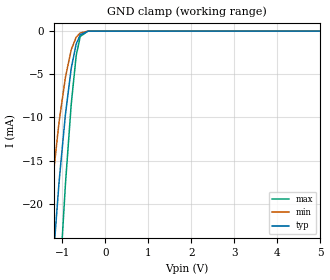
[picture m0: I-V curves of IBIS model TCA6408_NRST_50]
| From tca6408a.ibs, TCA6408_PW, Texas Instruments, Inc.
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[Model]   TCA6408_NRST_50
Model_type  Input
Vinl=1.35
Vinh=3.85
| variable   typ   min   max
C_comp   2.17pF   1.80pF   2.32pF
[Temperature Range]   40   100   -40
| Ambient temperature   25   85   -40
[Voltage range]   5   4.5   5.5
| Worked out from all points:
|   GND clamp passes 1 mA (typ) near -0.65 V on its own axis
[GND Clamp]
| TCA6408_NRST_50
|   Voltage   I(typ)   I(min)   I(max)
-5V       -421.5mA   -327.2mA   -555.2mA
-1.48V    -46.19mA   -30.98mA   -72.79mA
-1.435V   -42.57mA   -28.34mA   -67.61mA
-1.265V   -29.76mA   -19.1mA    -48.89mA
-1.085V   -17.96mA   -10.85mA   -30.98mA
-1.065V   -16.78mA   -10.05mA   -29.14mA
-930mV    -9.662mA   -5.357mA   -17.73mA
-795mV    -4.307mA   -2.154mA   -8.462mA
-680mV    -1.498mA   -708.4uA   -2.836mA
-585mV    -416.3uA   -213.5uA   -615.5uA
-405mV    -11.9uA    -9.596uA   -9.604uA
5V        572.5pA    2.003nA    91.86pA
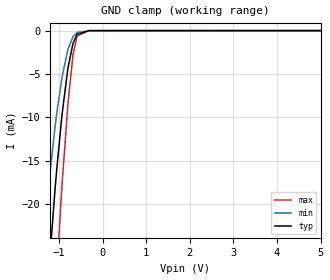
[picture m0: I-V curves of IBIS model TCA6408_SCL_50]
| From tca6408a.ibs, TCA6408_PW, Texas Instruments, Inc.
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[Model]   TCA6408_SCL_50
Model_type  Input
Vinl=1.35
Vinh=3.85
| variable   typ   min   max
C_comp   2.12pF   1.76pF   2.26pF
[Temperature Range]   40   100   -40
| Ambient temperature   25   85   -40
[Voltage range]   5   4.5   5.5
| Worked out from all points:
|   GND clamp passes 1 mA (typ) near -0.65 V on its own axis
[GND Clamp]
| TCA6408_SCL_50
|   Voltage   I(typ)   I(min)   I(max)
-5V       -421.5mA   -327.2mA   -555.2mA
-1.48V    -46.19mA   -30.98mA   -72.8mA
-1.435V   -42.58mA   -28.34mA   -67.61mA
-1.265V   -29.77mA   -19.11mA   -48.89mA
-1.085V   -17.96mA   -10.85mA   -30.98mA
-1.05V    -15.92mA   -9.467mA   -27.79mA
-930mV    -9.667mA   -5.361mA   -17.73mA
-795mV    -4.311mA   -2.158mA   -8.467mA
-680mV    -1.503mA   -712.6uA   -2.841mA
-585mV    -421uA     -217.3uA   -621uA
-310mV    -3.791uA   -3.288uA   -3.906uA
5V        572.5pA    3.503uA    -5.522uA
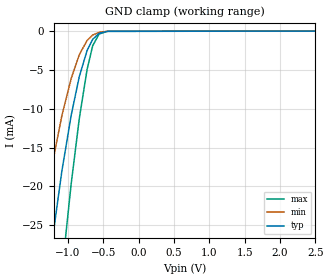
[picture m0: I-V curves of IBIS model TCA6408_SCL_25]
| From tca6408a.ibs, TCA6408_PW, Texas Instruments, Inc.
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[Model]   TCA6408_SCL_25
Model_type  Input
Vinl=0.69
Vinh=1.89
| variable   typ   min   max
C_comp   2.19pF   1.68pF   2.42pF
[Temperature Range]   40   100   -40
| Ambient temperature   25   85   -40
[Voltage range]   2.5   2.3   2.7
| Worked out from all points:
|   GND clamp passes 1 mA (typ) near -0.65 V on its own axis
[GND Clamp]
| TCA6408_SCL_25
|   Voltage   I(typ)   I(min)   I(max)
-2.5V     -143.4mA   -105mA     -204.1mA
-1.49V    -47.01mA   -31.58mA   -73.96mA
-1.46V    -44.57mA   -29.8mA    -70.48mA
-1.27V    -30.12mA   -19.36mA   -49.42mA
-1.085V   -17.96mA   -10.85mA   -30.98mA
-955mV    -10.86mA   -6.127mA   -19.7mA
-840mV    -5.87mA    -3.043mA   -11.28mA
-730mV    -2.509mA   -1.205mA   -4.961mA
-650mV    -1.053mA   -502.7uA   -1.883mA
-560mV    -279.8uA   -153.1uA   -377.5uA
-440mV    -30.06uA   -22.66uA   -28.84uA
2.5V      205.9pA    1.388uA    -2.198uA
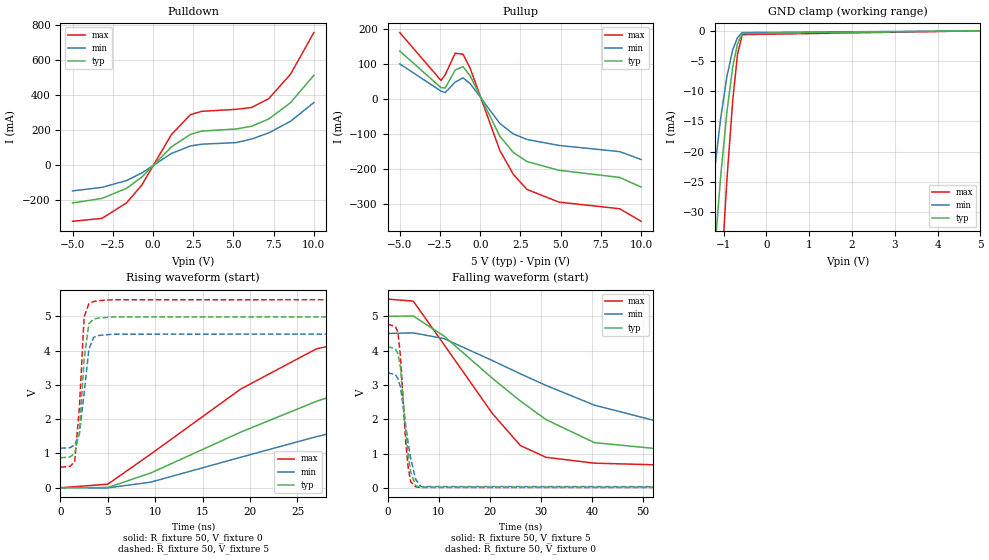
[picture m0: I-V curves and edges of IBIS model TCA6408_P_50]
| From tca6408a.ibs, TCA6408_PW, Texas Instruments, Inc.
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[Model]   TCA6408_P_50
Model_type  I/O
Vinl=1.35
Vinh=3.85
Enable   Active-Low
Vref =   0
Rref =   500
Cref =   50p
Vmeas =   2.5
| variable   typ   min   max
C_comp   3.63pF   2.93pF   3.99pF
| C_pullup   6.60pF   2.64pF   9.47pF
| C_pulldown   4.28pF   3.34pF   5.80pF
| C_tri-state   3.63pF   2.93pF   3.99pF
[Temperature Range]   40   100   -40
| Ambient temperature   25   85   -40
[Voltage range]   5   4.5   5.5
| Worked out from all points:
|   slope of the pulldown table from 0 to 0.75 V, typ, clamps not added: 10.5 ohm
|   slope of the pullup table from 0 to 0.75 V, typ, clamps not added: 10.5 ohm
|   GND clamp passes 1 mA (typ) near -0.61 V on its own axis
|   rising waveform, R_fixture 50, V_fixture 0: 20-80 % time 23.3ns typ, 32.9ns min, 15.6ns max; typ from 0 V to 4.12 V
|   falling waveform, R_fixture 50, V_fixture 5: 20-80 % time 21.2ns typ, 34.1ns min, 14.2ns max; typ from 5 V to 0.876 V
|   rising waveform, R_fixture 50, V_fixture 5: 20-80 % time 684ps typ, 812ps min, 654ps max; typ from 0.876 V to 5 V
|   falling waveform, R_fixture 50, V_fixture 0: 20-80 % time 1.53ns typ, 2.01ns min, 1.27ns max; typ from 4.12 V to 0 V
[GND Clamp]
| TCA6408_P_50
|   Voltage   I(typ)   I(min)   I(max)
-5V       -590mA     -448.8mA   -795mA
-1.51V    -68.12mA   -45.25mA   -108.4mA
-1.465V   -63.04mA   -41.61mA   -101mA
-1.29V    -44.47mA   -28.47mA   -73.42mA
-1.25V    -40.52mA   -25.71mA   -67.44mA
-1.075V   -24.76mA   -14.94mA   -43.03mA
-1.06V    -23.54mA   -14.13mA   -41.1mA
-920mV    -13.34mA   -7.513mA   -24.47mA
-785mV    -5.952mA   -3.123mA   -11.49mA
-675mV    -2.175mA   -1.137mA   -3.955mA
-565mV    -467.5uA   -292.1uA   -632uA
5V        1.249nA    3.317nA    448pA
[Pulldown]
| TCA6408_P_50
|   Voltage   I(typ)   I(min)   I(max)
-5V       -216.3mA   -147.4mA   -321.1mA
-3.17V    -190.5mA   -127.2mA   -304.5mA
-1.635V   -132.3mA   -88.14mA   -215.2mA
-695mV    -68.89mA   -45.25mA   -114.4mA
1.14V     103.7mA    66.3mA     173.6mA
2.33V     175.5mA    109.3mA    288.5mA
3.04V     194.5mA    119.6mA    307.4mA
5.175V    206.5mA    128.6mA    318.7mA
6.135V    222mA      148.8mA    329.3mA
7.2V      263.7mA    184.3mA    379.8mA
8.55V     356.6mA    250.3mA    519.1mA
10V       512.8mA    357.4mA    757.3mA
[Pullup]
| TCA6408_P_50
|   Voltage   I(typ)   I(min)   I(max)
-5V       135.9mA    99.31mA    188.6mA
-2.44V    31.7mA     21.81mA    52.05mA
-2.175V   30.45mA    17.66mA    68.46mA
-1.555V   81.88mA    47.36mA    129.8mA
-1.07V    91.37mA    59.47mA    127mA
-620mV    64.88mA    42.88mA    86.27mA
1.22V     -107.1mA   -70.5mA    -147.6mA
2.055V    -153mA     -100.3mA   -215.4mA
2.91V     -179.1mA   -116.2mA   -258.8mA
4.9V      -204mA     -133.2mA   -294.7mA
8.665V    -224.3mA   -150.7mA   -313.6mA
10V       -251.7mA   -173.2mA   -349.4mA
[Ramp]
| TCA6408_P_50
| variable   typ   min   max
dV/dt_r   2.50/2.35E-08   2.04/3.31E-08   2.90/1.57E-08
dV/dt_f   2.49/2.13E-08   2.02/3.41E-08   2.96/1.43E-08
R_load = 50
[Rising Waveform]
| TCA6408_P_50
R_fixture =   50
C_fixture =   0
L_fixture =   0
V_fixture =   0
V_fixture_min = 0
V_fixture_max = 0
|   Time   V(typ)   V(min)   V(max)
0s        3.746nV    27.75nV    804.2pV
5ns       9.165mV    -3.401mV   104.3mV
9.5ns     426.5mV    162mV      976.1mV
19ns      1.62V      887.4mV    2.876V
27ns      2.52V      1.49V      4.051V
33.5ns    3.109V     1.919V     4.439V
44.5ns    3.691V     2.497V     4.631V
67ns      3.99V      3.081V     4.732V
111ns     4.096V     3.3V       4.766V
520ns     4.118V     3.355V     4.771V
[Falling Waveform]
| TCA6408_P_50
R_fixture =   50
C_fixture =   0
L_fixture =   0
V_fixture =   5
V_fixture_min = 4.5
V_fixture_max = 5.5
|   Time   V(typ)   V(min)   V(max)
0s        5V         4.5V       5.5V
5ns       5.008V     4.516V     5.442V
11ns      4.426V     4.351V     4.182V
20.5ns    3.193V     3.71V      2.167V
26ns      2.53V      3.323V     1.231V
31ns      1.99V      2.986V     891.7mV
40.5ns    1.318V     2.409V     719.4mV
63.5ns    985mV      1.537V     628.3mV
105ns     896.1mV    1.237V     602.6mV
520ns     876.2mV    1.153V     598.2mV
[Rising Waveform]
| TCA6408_P_50
R_fixture =   50
C_fixture =   0
L_fixture =   0
V_fixture =   5
V_fixture_min = 4.5
V_fixture_max = 5.5
|   Time   V(typ)   V(min)   V(max)
0s        876.1mV    1.153V     598.2mV
1ns       895.7mV    1.166V     621.7mV
1.5ns     1V         1.25V      752.9mV
2ns       1.614V     1.569V     2.349V
2.5ns     3.752V     2.756V     4.982V
3ns       4.788V     4.04V      5.368V
3.5ns     4.916V     4.384V     5.431V
4ns       4.947V     4.44V      5.455V
5.5ns     4.979V     4.478V     5.481V
520ns     5V         4.5V       5.5V
[Falling Waveform]
| TCA6408_P_50
R_fixture =   50
C_fixture =   0
L_fixture =   0
V_fixture =   0
V_fixture_min = 0
V_fixture_max = 0
|   Time   V(typ)   V(min)   V(max)
0s        4.118V     3.355V     4.771V
1.5ns     4.05V      3.299V     4.702V
2ns       3.909V     3.188V     4.533V
2.5ns     3.511V     2.934V     3.832V
3.5ns     1.715V     1.853V     1.391V
4ns       983.7mV    1.311V     610.2mV
4.5ns     468.5mV    853.7mV    176.7mV
5.5ns     55.18mV    243.8mV    28.68mV
6.5ns     17.66mV    37.94mV    12.63mV
520ns     62.97nV    252nV      35.55nV
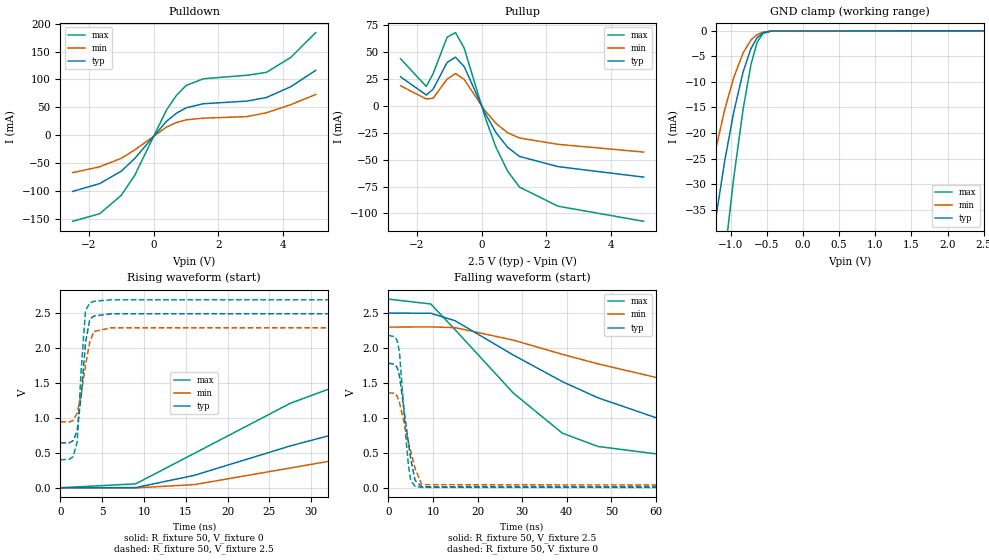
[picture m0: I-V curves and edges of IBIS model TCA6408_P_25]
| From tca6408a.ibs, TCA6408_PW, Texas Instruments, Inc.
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[Model]   TCA6408_P_25
Model_type  I/O
Vinl=0.69
Vinh=1.89
Enable   Active-Low
Vref =   0
Rref =   500
Cref =   50p
Vmeas =   1.25
| variable   typ   min   max
C_comp   3.69pF   2.93pF   4.10pF
| C_pullup   6.79pF   2.74pF   10.86pF
| C_pulldown   4.46pF   3.36pF   6.24pF
| C_tri-state   3.69pF   2.93pF   4.10pF
[Temperature Range]   40   100   -40
| Ambient temperature   25   85   -40
[Voltage range]   2.5   2.3   2.7
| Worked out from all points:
|   slope of the pulldown table from 0 to 0.375 V, typ, clamps not added: 15.6 ohm
|   slope of the pullup table from 0 to 0.375 V, typ, clamps not added: 17.4 ohm
|   GND clamp passes 1 mA (typ) near -0.61 V on its own axis
|   rising waveform, R_fixture 50, V_fixture 0: 20-80 % time 39.1ns typ, 55.9ns min, 24.3ns max; typ from 0 V to 1.78 V
|   falling waveform, R_fixture 50, V_fixture 2.5: 20-80 % time 37.3ns typ, 65.3ns min, 21.8ns max; typ from 2.5 V to 0.642 V
|   rising waveform, R_fixture 50, V_fixture 2.5: 20-80 % time 889ps typ, 1.16ns min, 722ps max; typ from 0.642 V to 2.5 V
|   falling waveform, R_fixture 50, V_fixture 0: 20-80 % time 2.26ns typ, 3.04ns min, 1.59ns max; typ from 1.78 V to 0 V
[GND Clamp]
| TCA6408_P_25
|   Voltage   I(typ)   I(min)   I(max)
-2.5V     -199.5mA   -143mA     -290.2mA
-1.495V   -66.41mA   -44.03mA   -105.9mA
-1.3V     -45.47mA   -29.17mA   -74.94mA
-1.275V   -42.97mA   -27.43mA   -71.16mA
-1.085V   -25.59mA   -15.5mA    -44.34mA
-960mV    -16.02mA   -9.208mA   -28.93mA
-830mV    -8.107mA   -4.347mA   -15.43mA
-720mV    -3.455mA   -1.786mA   -6.597mA
-635mV    -1.338mA   -725.2uA   -2.246mA
-555mV    -393.8uA   -252.8uA   -513.9uA
-435mV    -36.87uA   -30.65uA   -32.48uA
2.5V      522.1pA    1.492nA    -263.6pA
[Pulldown]
| TCA6408_P_25
|   Voltage   I(typ)   I(min)   I(max)
-2.5V     -100.3mA   -66.72mA   -153.8mA
-1.665V   -86.32mA   -56.23mA   -140.3mA
-995mV    -63.91mA   -40.95mA   -107mA
-580mV    -41.14mA   -25.84mA   -71.06mA
400mV     25.38mA    15.01mA    45.82mA
705mV     39.76mA    23.05mA    71.75mA
1.005V    49.41mA    27.82mA    89.36mA
1.53V     56.6mA     30.79mA    101.3mA
2.88V     61.37mA    33.64mA    107.6mA
3.48V     67.85mA    40.52mA    112.8mA
4.23V     87.1mA     55.01mA    139.6mA
5V        116.4mA    73.18mA    184mA
[Pullup]
| TCA6408_P_25
|   Voltage   I(typ)   I(min)   I(max)
-2.5V     27.05mA    18.71mA    43.88mA
-1.705V   10.14mA    6.404mA    18.04mA
-1.495V   15.53mA    7.156mA    29.94mA
-1.065V   40.3mA     24.79mA    63.75mA
-805mV    45.35mA    30.16mA    68.19mA
-535mV    36.51mA    24.55mA    53.62mA
105mV     -6.664mA   -4.379mA   -10.22mA
445mV     -24.83mA   -16.25mA   -38.52mA
805mV     -38.57mA   -24.98mA   -60.74mA
1.17V     -46.99mA   -29.85mA   -75.51mA
2.36V     -56.47mA   -35.74mA   -93.28mA
5V        -66.2mA    -42.93mA   -107.3mA
[Ramp]
| TCA6408_P_25
| variable   typ   min   max
dV/dt_r   1.09/3.93E-08   0.83/5.61E-08   1.33/2.46E-08
dV/dt_f   1.12/3.74E-08   0.82/6.54E-08   1.39/2.19E-08
R_load = 50
[Rising Waveform]
| TCA6408_P_25
R_fixture =   50
C_fixture =   0
L_fixture =   0
V_fixture =   0
V_fixture_min = 0
V_fixture_max = 0
|   Time   V(typ)   V(min)   V(max)
0s        1.68nV     12.67nV    504.7pV
9ns       2.519mV    -1.473mV   55.94mV
16ns      177mV      44.79mV    491mV
27.5ns    598.7mV    282.8mV    1.209V
40ns      995.2mV    542.7mV    1.762V
50.5ns    1.252V     725.2mV    1.987V
65.5ns    1.504V     926.8mV    2.099V
103ns     1.718V     1.206V     2.167V
156ns     1.773V     1.325V     2.181V
520ns     1.784V     1.361V     2.182V
[Falling Waveform]
| TCA6408_P_25
R_fixture =   50
C_fixture =   0
L_fixture =   0
V_fixture =   2.5
V_fixture_min = 2.3
V_fixture_max = 2.7
|   Time   V(typ)   V(min)   V(max)
0s        2.5V       2.3V       2.7V
9.5ns     2.498V     2.303V     2.631V
15ns      2.39V      2.292V     2.261V
28ns      1.901V     2.114V     1.358V
39ns      1.521V     1.911V     783.6mV
47ns      1.289V     1.774V     592.1mV
60.5ns    993.3mV    1.573V     482.8mV
92ns      733mV      1.256V     419.7mV
162ns     651mV      1.006V     402.6mV
520ns     642mV      944.6mV    401.5mV
[Rising Waveform]
| TCA6408_P_25
R_fixture =   50
C_fixture =   0
L_fixture =   0
V_fixture =   2.5
V_fixture_min = 2.3
V_fixture_max = 2.7
|   Time   V(typ)   V(min)   V(max)
0s        642mV      944.5mV    401.5mV
1ns       641.2mV    940.2mV    403.8mV
1.5ns     672.1mV    960.9mV    442.7mV
2ns       812.6mV    1.068V     654.7mV
2.5ns     1.335V     1.353V     1.719V
3ns       2.074V     1.753V     2.537V
3.5ns     2.406V     2.083V     2.644V
4ns       2.458V     2.237V     2.669V
6ns       2.49V      2.289V     2.69V
520ns     2.5V       2.3V       2.7V
[Falling Waveform]
| TCA6408_P_25
R_fixture =   50
C_fixture =   0
L_fixture =   0
V_fixture =   0
V_fixture_min = 0
V_fixture_max = 0
|   Time   V(typ)   V(min)   V(max)
0s        1.784V     1.361V     2.182V
1.5ns     1.767V     1.351V     2.161V
2ns       1.715V     1.308V     2.099V
2.5ns     1.599V     1.219V     1.937V
4ns       884.2mV    803.3mV    671.8mV
4.5ns     638.8mV    661.7mV    324.7mV
5ns       419.2mV    524.6mV    105.8mV
6ns       107.5mV    277.5mV    22.03mV
7.5ns     14.57mV    45.42mV    7.227mV
520ns     81.62nV    304.4nV    43.18nV
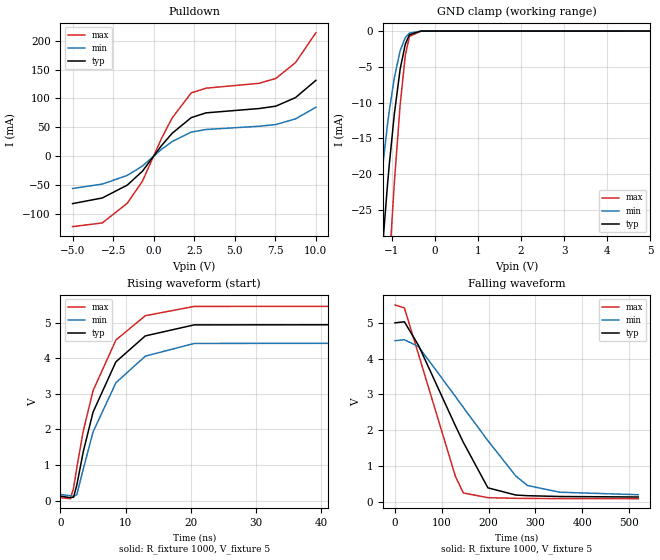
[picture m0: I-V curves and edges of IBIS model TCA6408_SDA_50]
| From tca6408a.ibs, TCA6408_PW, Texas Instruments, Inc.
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[Model]   TCA6408_SDA_50
Model_type  I/O_open_drain
Vinl=1.35
Vinh=3.85
Enable   Active-Low
Vref =   5
Rref =   1000
Cref =   50p
Vmeas =   2.5
| variable   typ   min   max
C_comp   3.07pF   2.23pF   3.44pF
| C_pulldown   1.95pF   0.78pF   2.55pF
| C_tri-state   3.07pF   2.23pF   3.44pF
[Temperature Range]   40   100   -40
| Ambient temperature   25   85   -40
[Voltage range]   5   4.5   5.5
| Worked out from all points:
|   slope of the pulldown table from 0 to 0.75 V, typ, clamps not added: 27.4 ohm
|   GND clamp passes 1 mA (typ) near -0.63 V on its own axis
|   rising waveform, R_fixture 1000, V_fixture 5: 20-80 % time 5.79ns typ, 6.26ns min, 5.42ns max; typ from 0.125 V to 5 V
|   falling waveform, R_fixture 1000, V_fixture 5: 20-80 % time 104ns typ, 146ns min, 74.6ns max; typ from 5 V to 0.129 V
[GND Clamp]
| TCA6408_SDA_50
|   Voltage   I(typ)   I(min)   I(max)
-5V       -485.9mA   -373.7mA   -646.7mA
-1.495V   -54.71mA   -36.56mA   -86.57mA
-1.45V    -50.53mA   -33.53mA   -80.53mA
-1.28V    -35.7mA    -22.93mA   -58.7mA
-1.09V    -21.25mA   -12.89mA   -36.66mA
-1.055V   -18.89mA   -11.29mA   -32.94mA
-935mV    -11.62mA   -6.534mA   -21.21mA
-800mV    -5.319mA   -2.744mA   -10.32mA
-680mV    -1.821mA   -907.7uA   -3.383mA
-585mV    -514.7uA   -286.1uA   -750.7uA
-315mV    -4.283uA   -3.819uA   -4.181uA
5V        768.1pA    3.503uA    -5.521uA
[Pulldown]
| TCA6408_SDA_50
|   Voltage   I(typ)   I(min)   I(max)
-5V       -82.45mA   -56.22mA   -122.3mA
-3.17V    -72.66mA   -48.53mA   -116mA
-1.63V    -50.38mA   -33.58mA   -81.84mA
-695mV    -26.29mA   -17.29mA   -43.61mA
470mV     17.72mA    11.43mA    29.85mA
1.135V    39.44mA    25.23mA    65.94mA
2.315V    66.7mA     41.58mA    109.6mA
3.235V    75mA       46.11mA    117.8mA
6.495V    82.46mA    51.74mA    126.2mA
7.53V     86.58mA    54.63mA    134.6mA
8.745V    101.4mA    64.52mA    162.1mA
10V       131.3mA    84.61mA    213.8mA
[Ramp]
| TCA6408_SDA_50
| variable   typ   min   max
dV/dt_r   2.95/5.80E-09   2.63/6.26E-09   3.27/5.42E-09
dV/dt_f   2.94/1.05E-07   2.60/1.47E-07   3.28/7.51E-08
R_load = 1000
[Rising Waveform]
| TCA6408_SDA_50
R_fixture =   1000
C_fixture =   0
L_fixture =   0
V_fixture =   5
V_fixture_min = 4.5
V_fixture_max = 5.5
|   Time   V(typ)   V(min)   V(max)
0s        124.5mV    171.8mV    81.52mV
1.5ns     81.82mV    137.7mV    52.73mV
2ns       91.96mV    115.1mV    337mV
2.5ns     427.7mV    165mV      915.6mV
3.5ns     1.377V     887.7mV    1.959V
5ns       2.488V     1.932V     3.091V
8.5ns     3.901V     3.312V     4.514V
13ns      4.629V     4.06V      5.197V
20.5ns    4.939V     4.417V     5.458V
520ns     5V         4.5V       5.5V
[Falling Waveform]
| TCA6408_SDA_50
R_fixture =   1000
C_fixture =   0
L_fixture =   0
V_fixture =   5
V_fixture_min = 4.5
V_fixture_max = 5.5
|   Time   V(typ)   V(min)   V(max)
0s        5V         4.5V       5.5V
20ns      5.028V     4.527V     5.415V
50.5ns    4.359V     4.33V      4.103V
129ns     2.122V     2.941V     708.7mV
146ns     1.657V     2.634V     242.9mV
198.5ns   386.5mV    1.706V     110.8mV
258ns     184.7mV    719.4mV    93.01mV
283ns     166.3mV    451.8mV    89.96mV
352ns     143.8mV    263.7mV    85.57mV
520ns     129.5mV    193.7mV    82.43mV
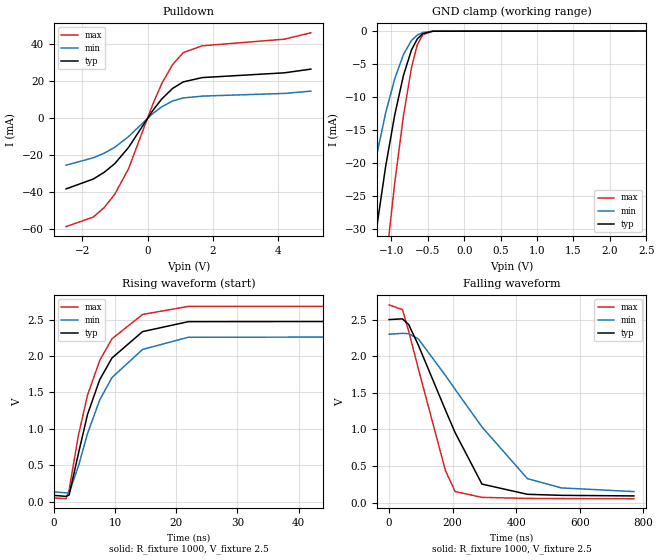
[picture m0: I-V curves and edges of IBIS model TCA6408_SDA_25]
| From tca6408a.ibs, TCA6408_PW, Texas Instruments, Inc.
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[Model]   TCA6408_SDA_25
Model_type  I/O_open_drain
Vinl=0.69
Vinh=1.89
Enable   Active-Low
Vref =   2.5
Rref =   1000
Cref =   50p
Vmeas =   1.25
| variable   typ   min   max
C_comp   3.07pF   2.07pF   3.54pF
| C_pulldown   1.93pF   0.80pF   2.67pF
| C_tri-state   3.07pF   2.07pF   3.54pF
[Temperature Range]   40   100   -40
| Ambient temperature   25   85   -40
[Voltage range]   2.5   2.3   2.7
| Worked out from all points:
|   slope of the pulldown table from 0 to 0.375 V, typ, clamps not added: 41 ohm
|   GND clamp passes 1 mA (typ) near -0.63 V on its own axis
|   rising waveform, R_fixture 1000, V_fixture 2.5: 20-80 % time 6.1ns typ, 6.8ns min, 5.64ns max; typ from 0.09 V to 2.5 V
|   falling waveform, R_fixture 1000, V_fixture 2.5: 20-80 % time 143ns typ, 217ns min, 96ns max; typ from 2.5 V to 0.092 V
[GND Clamp]
| TCA6408_SDA_25
|   Voltage   I(typ)   I(min)   I(max)
-2.5V     -164.9mA   -119.6mA   -237mA
-1.49V    -54.24mA   -36.22mA   -85.89mA
-1.46V    -51.45mA   -34.2mA    -81.86mA
-1.27V    -34.88mA   -22.35mA   -57.47mA
-1.08V    -20.56mA   -12.43mA   -35.58mA
-955mV    -12.73mA   -7.245mA   -23.03mA
-835mV    -6.732mA   -3.552mA   -12.86mA
-725mV    -2.878mA   -1.436mA   -5.585mA
-645mV    -1.203mA   -611.4uA   -2.091mA
-570mV    -404.1uA   -233uA     -558.9uA
-435mV    -32.77uA   -26.06uA   -30.49uA
2.5V      294.5pA    1.389uA    -2.198uA
[Pulldown]
| TCA6408_SDA_25
|   Voltage   I(typ)   I(min)   I(max)
-2.5V     -38.21mA   -25.41mA   -58.57mA
-1.665V   -32.88mA   -21.42mA   -53.42mA
-1.325V   -29.17mA   -18.87mA   -48.19mA
-1.005V   -24.53mA   -15.72mA   -41.01mA
-585mV    -15.82mA   -9.947mA   -27.3mA
150mV     3.947mA    2.363mA    7.134mA
430mV     10.3mA     6.081mA    18.57mA
765mV     16.04mA    9.25mA     28.93mA
1.09V     19.56mA    10.9mA     35.38mA
1.67V     21.89mA    11.89mA    39.05mA
4.19V     24.47mA    13.35mA    42.64mA
5V        26.46mA    14.57mA    46.07mA
[Ramp]
| TCA6408_SDA_25
| variable   typ   min   max
dV/dt_r   1.46/6.10E-09   1.31/6.81E-09   1.60/5.65E-09
dV/dt_f   1.45/1.44E-07   1.30/2.19E-07   1.60/9.67E-08
R_load = 1000
[Rising Waveform]
| TCA6408_SDA_25
R_fixture =   1000
C_fixture =   0
L_fixture =   0
V_fixture =   2.5
V_fixture_min = 2.3
V_fixture_max = 2.7
|   Time   V(typ)   V(min)   V(max)
0s        89.88mV    136.6mV    53.97mV
2ns       74.75mV    124.7mV    43.78mV
2.5ns     93.76mV    124.2mV    164.6mV
4ns       655.8mV    486.5mV    904.5mV
5.5ns     1.197V     935mV      1.462V
7.5ns     1.675V     1.398V     1.939V
9.5ns     1.972V     1.704V     2.236V
14.5ns    2.334V     2.09V      2.569V
22ns      2.471V     2.257V     2.68V
520ns     2.5V       2.3V       2.7V
[Falling Waveform]
| TCA6408_SDA_25
R_fixture =   1000
C_fixture =   0
L_fixture =   0
V_fixture =   2.5
V_fixture_min = 2.3
V_fixture_max = 2.7
|   Time   V(typ)   V(min)   V(max)
0s        2.5V       2.3V       2.7V
42ns      2.51V      2.312V     2.636V
61.5ns    2.432V     2.307V     2.341V
92ns      2.15V      2.235V     1.827V
177ns     1.265V     1.738V     440.2mV
207.5ns   957.5mV    1.547V     152.3mV
292ns     253.7mV    1.034V     72.29mV
435ns     114.2mV    327.8mV    58.01mV
542ns     100.1mV    201.5mV    55.58mV
770ns     92.05mV    151.3mV    54.23mV
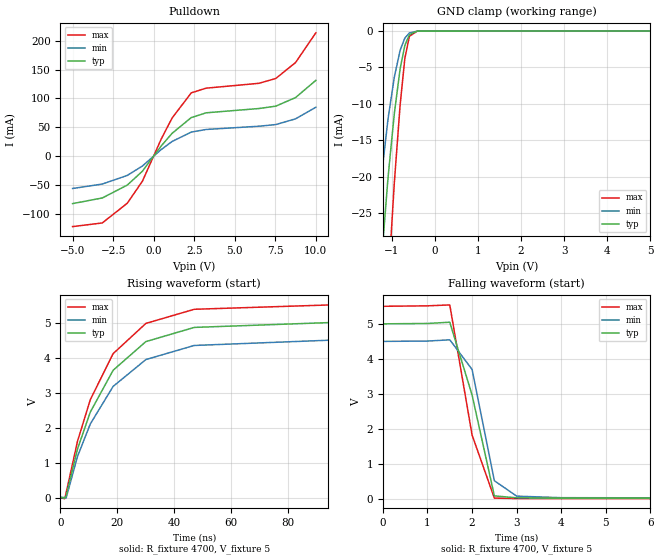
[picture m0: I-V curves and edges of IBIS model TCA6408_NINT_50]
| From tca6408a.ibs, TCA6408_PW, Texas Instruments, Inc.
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[Model]   TCA6408_NINT_50
Model_type  Open_drain
Enable   Active-Low
Vref =   5
Rref =   4700
Cref =   50p
Vmeas =   2.5
| variable   typ   min   max
C_comp   2.28pF   1.90pF   2.46pF
| C_pulldown   2.95pF   2.20pF   3.72pF
| C_tri-state   2.28pF   1.90pF   2.46pF
[Temperature Range]   40   100   -40
| Ambient temperature   25   85   -40
[Voltage range]   5   4.5   5.5
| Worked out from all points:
|   slope of the pulldown table from 0 to 0.75 V, typ, clamps not added: 27.4 ohm
|   GND clamp passes 1 mA (typ) near -0.63 V on its own axis
|   rising waveform, R_fixture 4700, V_fixture 5: 20-80 % time 17.8ns typ, 18.7ns min, 16.9ns max; typ from 0.027 V to 5 V
|   falling waveform, R_fixture 4700, V_fixture 5: 20-80 % time 588ps typ, 422ps min, 547ps max; typ from 5 V to 0.027 V
[GND Clamp]
| TCA6408_NINT_50
|   Voltage   I(typ)   I(min)   I(max)
-5V       -479.6mA   -367.9mA   -640.3mA
-1.495V   -53.75mA   -35.77mA   -85.47mA
-1.45V    -49.64mA   -32.8mA    -79.5mA
-1.28V    -35.02mA   -22.38mA   -57.9mA
-1.09V    -20.8mA    -12.54mA   -36.1mA
-1.07V    -19.46mA   -11.64mA   -33.99mA
-935mV    -11.34mA   -6.326mA   -20.84mA
-800mV    -5.162mA   -2.633mA   -10.11mA
-690mV    -1.955mA   -955.9uA   -3.719mA
-585mV    -489.4uA   -264.7uA   -718.6uA
-405mV    -14.02uA   -11.66uA   -11.19uA
5V        727.1pA    2.224nA    203.5pA
[Pulldown]
| TCA6408_NINT_50
|   Voltage   I(typ)   I(min)   I(max)
-5V       -82.53mA   -56.3mA    -122.4mA
-3.17V    -72.74mA   -48.6mA    -116.1mA
-1.63V    -50.43mA   -33.63mA   -81.91mA
-695mV    -26.31mA   -17.3mA    -43.63mA
465mV     17.55mA    11.31mA    29.55mA
1.13V     39.3mA     25.14mA    65.7mA
2.315V    66.7mA     41.58mA    109.6mA
3.235V    75mA       46.11mA    117.8mA
6.495V    82.46mA    51.74mA    126.2mA
7.53V     86.58mA    54.63mA    134.6mA
8.745V    101.4mA    64.52mA    162.1mA
10V       131.3mA    84.61mA    213.8mA
[Ramp]
| TCA6408_NINT_50
| variable   typ   min   max
dV/dt_r   3.00/1.78E-08   2.70/1.87E-08   3.31/1.69E-08
dV/dt_f   3.01/3.13E-10   2.71/3.95E-10   3.32/2.52E-10
R_load = 4700
[Rising Waveform]
| TCA6408_NINT_50
R_fixture =   4700
C_fixture =   0
L_fixture =   0
V_fixture =   5
V_fixture_min = 4.5
V_fixture_max = 5.5
|   Time   V(typ)   V(min)   V(max)
0s        26.77mV    37.14mV    17.43mV
1.5ns     11.55mV    26.23mV    -6.238mV
2ns       76.59mV    12.65mV    161.8mV
6ns       1.407V     1.196V     1.628V
10.5ns    2.457V     2.119V     2.81V
18.5ns    3.643V     3.184V     4.115V
30ns      4.457V     3.947V     4.974V
47ns      4.861V     4.348V     5.376V
94ns      4.997V     4.496V     5.498V
520ns     5V         4.5V       5.5V
[Falling Waveform]
| TCA6408_NINT_50
R_fixture =   4700
C_fixture =   0
L_fixture =   0
V_fixture =   5
V_fixture_min = 4.5
V_fixture_max = 5.5
|   Time   V(typ)   V(min)   V(max)
0s        5V         4.5V       5.5V
1ns       5.011V     4.509V     5.513V
1.5ns     5.046V     4.545V     5.539V
2ns       2.973V     3.701V     1.833V
2.5ns     98.49mV    529.8mV    33.55mV
3ns       41.28mV    90.26mV    22.47mV
4ns       30.22mV    46.1mV     18.82mV
9ns       26.9mV     37.42mV    17.48mV
520ns     26.77mV    37.14mV    17.43mV
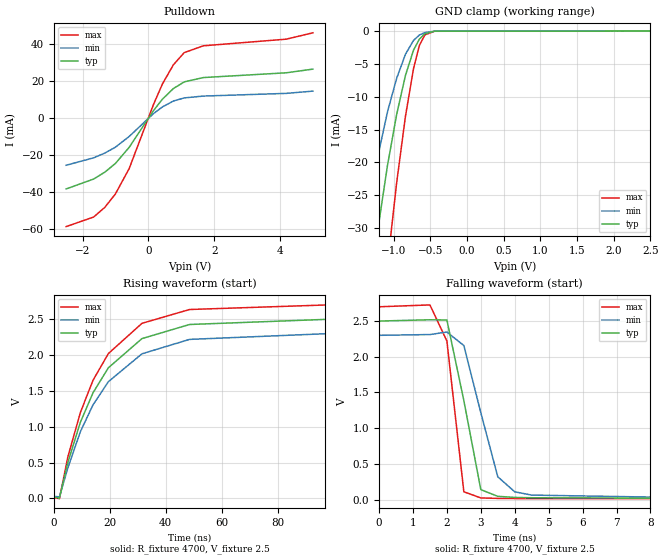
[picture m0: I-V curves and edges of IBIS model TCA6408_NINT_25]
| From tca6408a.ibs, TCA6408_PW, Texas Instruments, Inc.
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[Model]   TCA6408_NINT_25
Model_type  Open_drain
Enable   Active-Low
Vref =   2.5
Rref =   4700
Cref =   50p
Vmeas =   1.25
| variable   typ   min   max
C_comp   2.36pF   1.83pF   2.59pF
| C_pulldown   3.31pF   2.36pF   4.14pF
| C_tri-state   2.36pF   1.83pF   2.59pF
[Temperature Range]   40   100   -40
| Ambient temperature   25   85   -40
[Voltage range]   2.5   2.3   2.7
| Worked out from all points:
|   slope of the pulldown table from 0 to 0.375 V, typ, clamps not added: 41 ohm
|   GND clamp passes 1 mA (typ) near -0.63 V on its own axis
|   rising waveform, R_fixture 4700, V_fixture 2.5: 20-80 % time 18.5ns typ, 19.5ns min, 17.6ns max; typ from 0.019 V to 2.5 V
|   falling waveform, R_fixture 4700, V_fixture 2.5: 20-80 % time 623ps typ, 743ps min, 382ps max; typ from 2.5 V to 0.019 V
[GND Clamp]
| TCA6408_NINT_25
|   Voltage   I(typ)   I(min)   I(max)
-2.5V     -162.5mA   -117.5mA   -234.5mA
-1.495V   -53.75mA   -35.77mA   -85.47mA
-1.465V   -51mA      -33.78mA   -81.48mA
-1.275V   -34.61mA   -22.1mA    -57.29mA
-1.085V   -20.46mA   -12.31mA   -35.57mA
-960mV    -12.71mA   -7.198mA   -23.11mA
-840mV    -6.756mA   -3.54mA    -12.99mA
-730mV    -2.913mA   -1.434mA   -5.728mA
-650mV    -1.229mA   -608.9uA   -2.183mA
-575mV    -416.4uA   -230.2uA   -590.2uA
-445mV    -34.41uA   -26.43uA   -31.67uA
2.5V      278.2pA    863.6pA    98.69pA
[Pulldown]
| TCA6408_NINT_25
|   Voltage   I(typ)   I(min)   I(max)
-2.5V     -38.28mA   -25.48mA   -58.63mA
-1.665V   -32.94mA   -21.48mA   -53.47mA
-1.325V   -29.22mA   -18.91mA   -48.24mA
-1.005V   -24.56mA   -15.75mA   -41.05mA
-585mV    -15.83mA   -9.951mA   -27.3mA
150mV     3.947mA    2.363mA    7.134mA
425mV     10.19mA    6.023mA    18.39mA
760mV     15.97mA    9.213mA    28.81mA
1.09V     19.56mA    10.9mA     35.38mA
1.67V     21.89mA    11.89mA    39.05mA
4.19V     24.47mA    13.35mA    42.64mA
5V        26.46mA    14.57mA    46.07mA
[Ramp]
| TCA6408_NINT_25
| variable   typ   min   max
dV/dt_r   1.50/1.85E-08   1.37/1.95E-08   1.63/1.76E-08
dV/dt_f   1.52/4.48E-10   1.39/6.81E-10   1.64/3.24E-10
R_load = 4700
[Rising Waveform]
| TCA6408_NINT_25
R_fixture =   4700
C_fixture =   0
L_fixture =   0
V_fixture =   2.5
V_fixture_min = 2.3
V_fixture_max = 2.7
|   Time   V(typ)   V(min)   V(max)
0s        19.28mV    29.42mV    11.52mV
2ns       3.79mV     21.48mV    -3.645mV
5ns       500.9mV    424.3mV    578.2mV
9.5ns     1.064V     932.5mV    1.2V
14ns      1.474V     1.305V     1.648V
19.5ns    1.823V     1.629V     2.022V
31.5ns    2.23V      2.018V     2.443V
48.5ns    2.427V     2.219V     2.636V
97ns      2.498V     2.298V     2.699V
520ns     2.5V       2.3V       2.7V
[Falling Waveform]
| TCA6408_NINT_25
R_fixture =   4700
C_fixture =   0
L_fixture =   0
V_fixture =   2.5
V_fixture_min = 2.3
V_fixture_max = 2.7
|   Time   V(typ)   V(min)   V(max)
0s        2.5V       2.3V       2.7V
1.5ns     2.518V     2.311V     2.726V
2ns       2.515V     2.346V     2.22V
2.5ns     1.385V     2.157V     108.8mV
3ns       138.3mV    1.216V     22.09mV
3.5ns     44.82mV    318.6mV    15.68mV
4ns       29.45mV    107.9mV    13.67mV
4.5ns     24.51mV    61.84mV    12.74mV
8.5ns     19.52mV    30.38mV    11.59mV
520ns     19.28mV    29.42mV    11.52mV
